VERSION 5.7 ;
  NOWIREEXTENSIONATPIN ON ;
  DIVIDERCHAR "/" ;
  BUSBITCHARS "[]" ;
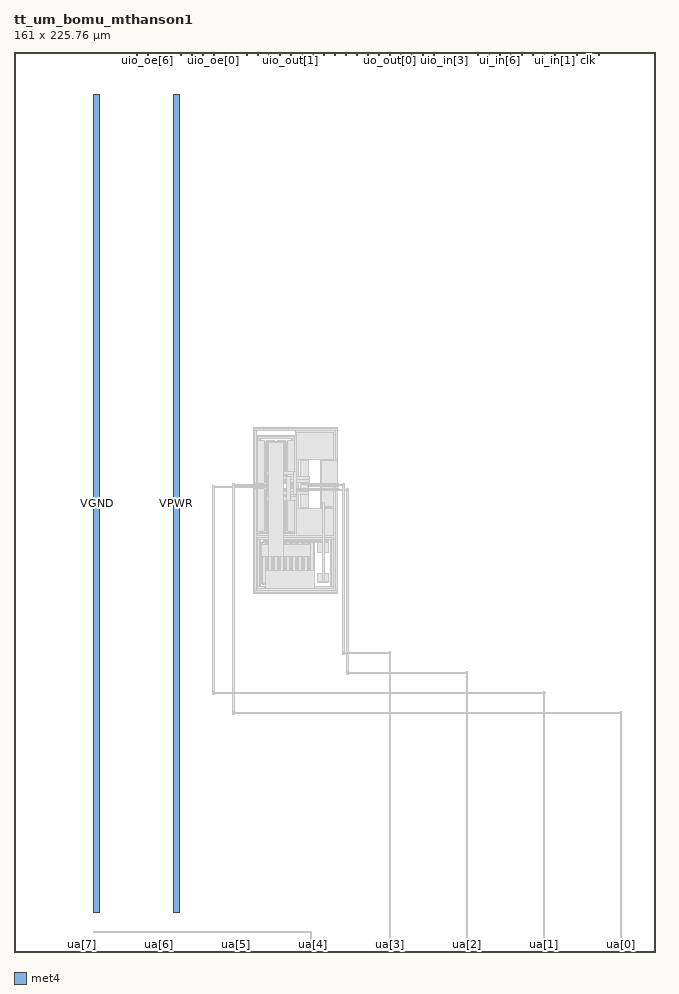
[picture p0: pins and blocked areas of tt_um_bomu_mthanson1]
MACRO tt_um_bomu_mthanson1
  CLASS BLOCK ;
  FOREIGN tt_um_bomu_mthanson1 ;
  ORIGIN 0.000 0.000 ;
  SIZE 161.000 BY 225.760 ;
  PIN clk
    DIRECTION INPUT ;
    USE SIGNAL ;
    PORT
      LAYER met4 ;
        RECT 143.830 224.760 144.130 225.760 ;
    END
  END clk
  PIN ena
    DIRECTION INPUT ;
    USE SIGNAL ;
    PORT
      LAYER met4 ;
        RECT 146.590 224.760 146.890 225.760 ;
    END
  END ena
  PIN rst_n
    DIRECTION INPUT ;
    USE SIGNAL ;
    PORT
      LAYER met4 ;
        RECT 141.070 224.760 141.370 225.760 ;
    END
  END rst_n
  PIN ua[0]
    DIRECTION INOUT ;
    USE SIGNAL ;
    ANTENNAGATEAREA 12.000000 ;
    PORT
      LAYER met4 ;
        RECT 151.810 0.000 152.710 1.000 ;
    END
  END ua[0]
  PIN ua[1]
    DIRECTION INOUT ;
    USE SIGNAL ;
    ANTENNAGATEAREA 12.000000 ;
    PORT
      LAYER met4 ;
        RECT 132.490 0.000 133.390 1.000 ;
    END
  END ua[1]
  PIN ua[2]
    DIRECTION INOUT ;
    USE SIGNAL ;
    ANTENNADIFFAREA 19.000000 ;
    PORT
      LAYER met4 ;
        RECT 113.170 0.000 114.070 1.000 ;
    END
  END ua[2]
  PIN ua[3]
    DIRECTION INOUT ;
    USE SIGNAL ;
    ANTENNADIFFAREA 19.000000 ;
    PORT
      LAYER met4 ;
        RECT 93.850 0.000 94.750 1.000 ;
    END
  END ua[3]
  PIN ua[4]
    DIRECTION INOUT ;
    USE SIGNAL ;
    PORT
      LAYER met4 ;
        RECT 74.530 0.000 75.430 1.000 ;
    END
  END ua[4]
  PIN ua[5]
    DIRECTION INOUT ;
    USE SIGNAL ;
    PORT
      LAYER met4 ;
        RECT 55.210 0.000 56.110 1.000 ;
    END
  END ua[5]
  PIN ua[6]
    DIRECTION INOUT ;
    USE SIGNAL ;
    PORT
      LAYER met4 ;
        RECT 35.890 0.000 36.790 1.000 ;
    END
  END ua[6]
  PIN ua[7]
    DIRECTION INOUT ;
    USE SIGNAL ;
    PORT
      LAYER met4 ;
        RECT 16.570 0.000 17.470 1.000 ;
    END
  END ua[7]
  PIN ui_in[0]
    DIRECTION INPUT ;
    USE SIGNAL ;
    PORT
      LAYER met4 ;
        RECT 138.310 224.760 138.610 225.760 ;
    END
  END ui_in[0]
  PIN ui_in[1]
    DIRECTION INPUT ;
    USE SIGNAL ;
    PORT
      LAYER met4 ;
        RECT 135.550 224.760 135.850 225.760 ;
    END
  END ui_in[1]
  PIN ui_in[2]
    DIRECTION INPUT ;
    USE SIGNAL ;
    PORT
      LAYER met4 ;
        RECT 132.790 224.760 133.090 225.760 ;
    END
  END ui_in[2]
  PIN ui_in[3]
    DIRECTION INPUT ;
    USE SIGNAL ;
    PORT
      LAYER met4 ;
        RECT 130.030 224.760 130.330 225.760 ;
    END
  END ui_in[3]
  PIN ui_in[4]
    DIRECTION INPUT ;
    USE SIGNAL ;
    PORT
      LAYER met4 ;
        RECT 127.270 224.760 127.570 225.760 ;
    END
  END ui_in[4]
  PIN ui_in[5]
    DIRECTION INPUT ;
    USE SIGNAL ;
    PORT
      LAYER met4 ;
        RECT 124.510 224.760 124.810 225.760 ;
    END
  END ui_in[5]
  PIN ui_in[6]
    DIRECTION INPUT ;
    USE SIGNAL ;
    PORT
      LAYER met4 ;
        RECT 121.750 224.760 122.050 225.760 ;
    END
  END ui_in[6]
  PIN ui_in[7]
    DIRECTION INPUT ;
    USE SIGNAL ;
    PORT
      LAYER met4 ;
        RECT 118.990 224.760 119.290 225.760 ;
    END
  END ui_in[7]
  PIN uio_in[0]
    DIRECTION INPUT ;
    USE SIGNAL ;
    PORT
      LAYER met4 ;
        RECT 116.230 224.760 116.530 225.760 ;
    END
  END uio_in[0]
  PIN uio_in[1]
    DIRECTION INPUT ;
    USE SIGNAL ;
    PORT
      LAYER met4 ;
        RECT 113.470 224.760 113.770 225.760 ;
    END
  END uio_in[1]
  PIN uio_in[2]
    DIRECTION INPUT ;
    USE SIGNAL ;
    PORT
      LAYER met4 ;
        RECT 110.710 224.760 111.010 225.760 ;
    END
  END uio_in[2]
  PIN uio_in[3]
    DIRECTION INPUT ;
    USE SIGNAL ;
    PORT
      LAYER met4 ;
        RECT 107.950 224.760 108.250 225.760 ;
    END
  END uio_in[3]
  PIN uio_in[4]
    DIRECTION INPUT ;
    USE SIGNAL ;
    PORT
      LAYER met4 ;
        RECT 105.190 224.760 105.490 225.760 ;
    END
  END uio_in[4]
  PIN uio_in[5]
    DIRECTION INPUT ;
    USE SIGNAL ;
    PORT
      LAYER met4 ;
        RECT 102.430 224.760 102.730 225.760 ;
    END
  END uio_in[5]
  PIN uio_in[6]
    DIRECTION INPUT ;
    USE SIGNAL ;
    PORT
      LAYER met4 ;
        RECT 99.670 224.760 99.970 225.760 ;
    END
  END uio_in[6]
  PIN uio_in[7]
    DIRECTION INPUT ;
    USE SIGNAL ;
    PORT
      LAYER met4 ;
        RECT 96.910 224.760 97.210 225.760 ;
    END
  END uio_in[7]
  PIN uio_oe[0]
    DIRECTION OUTPUT ;
    USE SIGNAL ;
    PORT
      LAYER met4 ;
        RECT 49.990 224.760 50.290 225.760 ;
    END
  END uio_oe[0]
  PIN uio_oe[1]
    DIRECTION OUTPUT ;
    USE SIGNAL ;
    PORT
      LAYER met4 ;
        RECT 47.230 224.760 47.530 225.760 ;
    END
  END uio_oe[1]
  PIN uio_oe[2]
    DIRECTION OUTPUT ;
    USE SIGNAL ;
    PORT
      LAYER met4 ;
        RECT 44.470 224.760 44.770 225.760 ;
    END
  END uio_oe[2]
  PIN uio_oe[3]
    DIRECTION OUTPUT ;
    USE SIGNAL ;
    PORT
      LAYER met4 ;
        RECT 41.710 224.760 42.010 225.760 ;
    END
  END uio_oe[3]
  PIN uio_oe[4]
    DIRECTION OUTPUT ;
    USE SIGNAL ;
    PORT
      LAYER met4 ;
        RECT 38.950 224.760 39.250 225.760 ;
    END
  END uio_oe[4]
  PIN uio_oe[5]
    DIRECTION OUTPUT ;
    USE SIGNAL ;
    PORT
      LAYER met4 ;
        RECT 36.190 224.760 36.490 225.760 ;
    END
  END uio_oe[5]
  PIN uio_oe[6]
    DIRECTION OUTPUT ;
    USE SIGNAL ;
    PORT
      LAYER met4 ;
        RECT 33.430 224.760 33.730 225.760 ;
    END
  END uio_oe[6]
  PIN uio_oe[7]
    DIRECTION OUTPUT ;
    USE SIGNAL ;
    PORT
      LAYER met4 ;
        RECT 30.670 224.760 30.970 225.760 ;
    END
  END uio_oe[7]
  PIN uio_out[0]
    DIRECTION OUTPUT ;
    USE SIGNAL ;
    PORT
      LAYER met4 ;
        RECT 72.070 224.760 72.370 225.760 ;
    END
  END uio_out[0]
  PIN uio_out[1]
    DIRECTION OUTPUT ;
    USE SIGNAL ;
    PORT
      LAYER met4 ;
        RECT 69.310 224.760 69.610 225.760 ;
    END
  END uio_out[1]
  PIN uio_out[2]
    DIRECTION OUTPUT ;
    USE SIGNAL ;
    PORT
      LAYER met4 ;
        RECT 66.550 224.760 66.850 225.760 ;
    END
  END uio_out[2]
  PIN uio_out[3]
    DIRECTION OUTPUT ;
    USE SIGNAL ;
    PORT
      LAYER met4 ;
        RECT 63.790 224.760 64.090 225.760 ;
    END
  END uio_out[3]
  PIN uio_out[4]
    DIRECTION OUTPUT ;
    USE SIGNAL ;
    PORT
      LAYER met4 ;
        RECT 61.030 224.760 61.330 225.760 ;
    END
  END uio_out[4]
  PIN uio_out[5]
    DIRECTION OUTPUT ;
    USE SIGNAL ;
    PORT
      LAYER met4 ;
        RECT 58.270 224.760 58.570 225.760 ;
    END
  END uio_out[5]
  PIN uio_out[6]
    DIRECTION OUTPUT ;
    USE SIGNAL ;
    PORT
      LAYER met4 ;
        RECT 55.510 224.760 55.810 225.760 ;
    END
  END uio_out[6]
  PIN uio_out[7]
    DIRECTION OUTPUT ;
    USE SIGNAL ;
    PORT
      LAYER met4 ;
        RECT 52.750 224.760 53.050 225.760 ;
    END
  END uio_out[7]
  PIN uo_out[0]
    DIRECTION OUTPUT ;
    USE SIGNAL ;
    PORT
      LAYER met4 ;
        RECT 94.150 224.760 94.450 225.760 ;
    END
  END uo_out[0]
  PIN uo_out[1]
    DIRECTION OUTPUT ;
    USE SIGNAL ;
    PORT
      LAYER met4 ;
        RECT 91.390 224.760 91.690 225.760 ;
    END
  END uo_out[1]
  PIN uo_out[2]
    DIRECTION OUTPUT ;
    USE SIGNAL ;
    PORT
      LAYER met4 ;
        RECT 88.630 224.760 88.930 225.760 ;
    END
  END uo_out[2]
  PIN uo_out[3]
    DIRECTION OUTPUT ;
    USE SIGNAL ;
    PORT
      LAYER met4 ;
        RECT 85.870 224.760 86.170 225.760 ;
    END
  END uo_out[3]
  PIN uo_out[4]
    DIRECTION OUTPUT ;
    USE SIGNAL ;
    PORT
      LAYER met4 ;
        RECT 83.110 224.760 83.410 225.760 ;
    END
  END uo_out[4]
  PIN uo_out[5]
    DIRECTION OUTPUT ;
    USE SIGNAL ;
    PORT
      LAYER met4 ;
        RECT 80.350 224.760 80.650 225.760 ;
    END
  END uo_out[5]
  PIN uo_out[6]
    DIRECTION OUTPUT ;
    USE SIGNAL ;
    PORT
      LAYER met4 ;
        RECT 77.590 224.760 77.890 225.760 ;
    END
  END uo_out[6]
  PIN uo_out[7]
    DIRECTION OUTPUT ;
    USE SIGNAL ;
    PORT
      LAYER met4 ;
        RECT 74.830 224.760 75.130 225.760 ;
    END
  END uo_out[7]
  PIN VGND
    USE GROUND ;
    PORT
      LAYER met4 ;
        RECT 20.000 10.000 21.500 215.000 ;
    END
  END VGND
  PIN VPWR
    USE POWER ;
    PORT
      LAYER met4 ;
        RECT 40.000 10.000 41.500 215.000 ;
    END
  END VPWR
  OBS
      LAYER pwell ;
        RECT 60.090 130.700 81.260 131.460 ;
        RECT 60.090 129.520 60.850 130.700 ;
        RECT 70.670 129.700 81.260 130.700 ;
        RECT 70.670 129.520 71.430 129.700 ;
        RECT 60.090 128.760 71.430 129.520 ;
        RECT 60.090 105.140 61.820 128.760 ;
        RECT 62.065 117.820 63.055 128.080 ;
        RECT 63.185 117.820 65.655 128.080 ;
        RECT 65.785 117.820 68.255 128.080 ;
        RECT 68.385 117.820 69.375 128.080 ;
        RECT 62.065 105.820 63.055 116.080 ;
        RECT 63.185 105.820 65.655 116.080 ;
        RECT 65.785 105.820 68.255 116.080 ;
        RECT 68.385 105.820 69.375 116.080 ;
        RECT 69.610 105.140 71.430 128.760 ;
        RECT 79.500 105.140 81.260 129.700 ;
        RECT 60.090 103.380 81.260 105.140 ;
        RECT 60.090 91.760 61.825 103.380 ;
        RECT 62.065 92.440 63.405 102.700 ;
        RECT 63.565 92.440 64.905 102.700 ;
        RECT 65.065 92.440 66.405 102.700 ;
        RECT 66.565 92.440 67.905 102.700 ;
        RECT 68.065 92.440 69.405 102.700 ;
        RECT 69.565 92.440 70.905 102.700 ;
        RECT 71.065 92.440 72.405 102.700 ;
        RECT 72.565 92.440 73.905 102.700 ;
        RECT 74.065 92.440 75.405 102.700 ;
        RECT 79.495 91.760 81.260 103.380 ;
        RECT 60.090 90.000 81.260 91.760 ;
      LAYER li1 ;
        RECT 60.220 130.830 81.130 131.330 ;
        RECT 60.220 90.630 60.720 130.830 ;
        RECT 70.800 129.830 80.130 130.330 ;
        RECT 61.190 128.890 70.240 129.390 ;
        RECT 61.190 105.010 61.690 128.890 ;
        RECT 62.340 128.140 62.780 128.310 ;
        RECT 63.460 128.140 65.380 128.310 ;
        RECT 66.060 128.140 67.980 128.310 ;
        RECT 68.660 128.140 69.100 128.310 ;
        RECT 62.255 117.930 62.425 127.970 ;
        RECT 62.695 117.930 62.865 127.970 ;
        RECT 63.375 117.930 63.545 127.970 ;
        RECT 63.855 117.930 64.025 127.970 ;
        RECT 64.335 117.930 64.505 127.970 ;
        RECT 64.815 117.930 64.985 127.970 ;
        RECT 65.295 117.930 65.465 127.970 ;
        RECT 65.975 117.930 66.145 127.970 ;
        RECT 66.455 117.930 66.625 127.970 ;
        RECT 66.935 117.930 67.105 127.970 ;
        RECT 67.415 117.930 67.585 127.970 ;
        RECT 67.895 117.930 68.065 127.970 ;
        RECT 68.575 117.930 68.745 127.970 ;
        RECT 69.015 117.930 69.185 127.970 ;
        RECT 62.340 117.590 62.780 117.760 ;
        RECT 63.460 117.590 65.380 117.760 ;
        RECT 66.060 117.590 67.980 117.760 ;
        RECT 68.660 117.590 69.100 117.760 ;
        RECT 62.340 116.140 62.780 116.310 ;
        RECT 63.460 116.140 65.380 116.310 ;
        RECT 66.060 116.140 67.980 116.310 ;
        RECT 68.660 116.140 69.100 116.310 ;
        RECT 62.255 105.930 62.425 115.970 ;
        RECT 62.695 105.930 62.865 115.970 ;
        RECT 63.375 105.930 63.545 115.970 ;
        RECT 63.855 105.930 64.025 115.970 ;
        RECT 64.335 105.930 64.505 115.970 ;
        RECT 64.815 105.930 64.985 115.970 ;
        RECT 65.295 105.930 65.465 115.970 ;
        RECT 65.975 105.930 66.145 115.970 ;
        RECT 66.455 105.930 66.625 115.970 ;
        RECT 66.935 105.930 67.105 115.970 ;
        RECT 67.415 105.930 67.585 115.970 ;
        RECT 67.895 105.930 68.065 115.970 ;
        RECT 68.575 105.930 68.745 115.970 ;
        RECT 69.015 105.930 69.185 115.970 ;
        RECT 62.340 105.590 62.780 105.760 ;
        RECT 63.460 105.590 65.380 105.760 ;
        RECT 66.060 105.590 67.980 105.760 ;
        RECT 68.660 105.590 69.100 105.760 ;
        RECT 69.740 105.010 70.240 128.890 ;
        RECT 61.190 104.510 70.240 105.010 ;
        RECT 70.800 105.010 71.300 129.830 ;
        RECT 71.800 123.600 73.960 129.330 ;
        RECT 76.970 123.600 79.130 129.330 ;
        RECT 71.800 117.570 73.960 123.300 ;
        RECT 76.970 117.570 79.130 123.300 ;
        RECT 71.800 111.540 73.960 117.270 ;
        RECT 76.970 111.540 79.130 117.270 ;
        RECT 71.800 105.510 73.960 111.240 ;
        RECT 76.970 105.510 79.130 111.240 ;
        RECT 79.630 105.010 80.130 129.830 ;
        RECT 70.800 104.510 80.130 105.010 ;
        RECT 61.195 103.510 80.125 104.010 ;
        RECT 61.195 91.630 61.695 103.510 ;
        RECT 62.340 102.760 63.130 102.930 ;
        RECT 63.840 102.760 64.630 102.930 ;
        RECT 65.340 102.760 66.130 102.930 ;
        RECT 66.840 102.760 67.630 102.930 ;
        RECT 68.340 102.760 69.130 102.930 ;
        RECT 69.840 102.760 70.630 102.930 ;
        RECT 71.340 102.760 72.130 102.930 ;
        RECT 72.840 102.760 73.630 102.930 ;
        RECT 74.340 102.760 75.130 102.930 ;
        RECT 62.255 92.550 62.425 102.590 ;
        RECT 63.045 92.550 63.215 102.590 ;
        RECT 63.755 92.550 63.925 102.590 ;
        RECT 64.545 92.550 64.715 102.590 ;
        RECT 65.255 92.550 65.425 102.590 ;
        RECT 66.045 92.550 66.215 102.590 ;
        RECT 66.755 92.550 66.925 102.590 ;
        RECT 67.545 92.550 67.715 102.590 ;
        RECT 68.255 92.550 68.425 102.590 ;
        RECT 69.045 92.550 69.215 102.590 ;
        RECT 69.755 92.550 69.925 102.590 ;
        RECT 70.545 92.550 70.715 102.590 ;
        RECT 71.255 92.550 71.425 102.590 ;
        RECT 72.045 92.550 72.215 102.590 ;
        RECT 72.755 92.550 72.925 102.590 ;
        RECT 73.545 92.550 73.715 102.590 ;
        RECT 74.255 92.550 74.425 102.590 ;
        RECT 75.045 92.550 75.215 102.590 ;
        RECT 76.025 100.200 78.875 102.360 ;
        RECT 76.025 92.770 78.875 94.930 ;
        RECT 62.340 92.210 63.130 92.380 ;
        RECT 63.840 92.210 64.630 92.380 ;
        RECT 65.340 92.210 66.130 92.380 ;
        RECT 66.840 92.210 67.630 92.380 ;
        RECT 68.340 92.210 69.130 92.380 ;
        RECT 69.840 92.210 70.630 92.380 ;
        RECT 71.340 92.210 72.130 92.380 ;
        RECT 72.840 92.210 73.630 92.380 ;
        RECT 74.340 92.210 75.130 92.380 ;
        RECT 79.625 91.630 80.125 103.510 ;
        RECT 61.195 91.130 80.125 91.630 ;
        RECT 80.630 90.630 81.130 130.830 ;
        RECT 60.220 90.130 81.130 90.630 ;
      LAYER met1 ;
        RECT 60.220 130.830 81.130 131.330 ;
        RECT 60.220 117.510 60.720 130.830 ;
        RECT 61.190 117.510 62.925 128.390 ;
        RECT 63.555 128.310 63.845 128.340 ;
        RECT 64.035 128.310 64.325 128.340 ;
        RECT 64.515 128.310 64.805 128.340 ;
        RECT 64.995 128.310 65.285 128.340 ;
        RECT 66.155 128.310 66.445 128.340 ;
        RECT 66.635 128.310 66.925 128.340 ;
        RECT 67.115 128.310 67.405 128.340 ;
        RECT 67.595 128.310 67.885 128.340 ;
        RECT 63.460 128.140 65.380 128.310 ;
        RECT 66.060 128.140 67.980 128.310 ;
        RECT 63.555 128.110 63.845 128.140 ;
        RECT 64.035 128.110 64.325 128.140 ;
        RECT 64.515 128.110 64.805 128.140 ;
        RECT 64.995 128.110 65.285 128.140 ;
        RECT 66.155 128.110 66.445 128.140 ;
        RECT 66.635 128.110 66.925 128.140 ;
        RECT 67.115 128.110 67.405 128.140 ;
        RECT 67.595 128.110 67.885 128.140 ;
        RECT 63.345 120.550 63.575 127.950 ;
        RECT 63.825 127.700 64.055 127.950 ;
        RECT 63.780 124.140 64.100 127.700 ;
        RECT 63.300 119.750 63.620 120.550 ;
        RECT 63.345 117.950 63.575 119.750 ;
        RECT 63.825 117.950 64.055 124.140 ;
        RECT 64.305 120.550 64.535 127.950 ;
        RECT 64.785 127.700 65.015 127.950 ;
        RECT 64.740 124.140 65.060 127.700 ;
        RECT 64.260 119.750 64.580 120.550 ;
        RECT 64.305 117.950 64.535 119.750 ;
        RECT 64.785 117.950 65.015 124.140 ;
        RECT 65.265 120.550 65.495 127.950 ;
        RECT 65.220 119.750 65.540 120.550 ;
        RECT 65.265 117.950 65.495 119.750 ;
        RECT 65.945 119.250 66.175 127.950 ;
        RECT 66.425 127.700 66.655 127.950 ;
        RECT 66.380 124.140 66.700 127.700 ;
        RECT 65.900 118.450 66.220 119.250 ;
        RECT 65.945 117.950 66.175 118.450 ;
        RECT 66.425 117.950 66.655 124.140 ;
        RECT 66.905 119.250 67.135 127.950 ;
        RECT 67.385 127.700 67.615 127.950 ;
        RECT 67.340 124.140 67.660 127.700 ;
        RECT 66.860 118.450 67.180 119.250 ;
        RECT 66.905 117.950 67.135 118.450 ;
        RECT 67.385 117.950 67.615 124.140 ;
        RECT 67.865 119.250 68.095 127.950 ;
        RECT 67.820 118.450 68.140 119.250 ;
        RECT 67.865 117.950 68.095 118.450 ;
        RECT 63.555 117.760 63.845 117.790 ;
        RECT 64.035 117.760 64.325 117.790 ;
        RECT 64.500 117.760 64.820 117.810 ;
        RECT 64.995 117.760 65.285 117.790 ;
        RECT 66.155 117.760 66.445 117.790 ;
        RECT 66.635 117.760 66.925 117.790 ;
        RECT 67.115 117.760 67.405 117.790 ;
        RECT 67.595 117.760 67.885 117.790 ;
        RECT 63.460 117.590 65.380 117.760 ;
        RECT 66.060 117.590 67.980 117.760 ;
        RECT 63.555 117.560 63.845 117.590 ;
        RECT 64.035 117.560 64.325 117.590 ;
        RECT 64.500 117.490 64.820 117.590 ;
        RECT 64.995 117.560 65.285 117.590 ;
        RECT 66.155 117.560 66.445 117.590 ;
        RECT 66.635 117.560 67.405 117.590 ;
        RECT 67.595 117.560 67.885 117.590 ;
        RECT 54.800 117.280 55.400 117.480 ;
        RECT 66.860 117.340 67.180 117.560 ;
        RECT 68.515 117.510 70.240 128.390 ;
        RECT 70.800 123.600 80.130 130.330 ;
        RECT 80.630 123.810 81.130 130.830 ;
        RECT 80.630 123.300 81.130 123.310 ;
        RECT 77.060 123.280 81.130 123.300 ;
        RECT 71.860 117.590 73.905 123.280 ;
        RECT 77.025 117.590 81.130 123.280 ;
        RECT 60.000 117.280 67.180 117.340 ;
        RECT 54.800 117.080 67.180 117.280 ;
        RECT 77.060 117.310 81.130 117.590 ;
        RECT 77.060 117.250 80.230 117.310 ;
        RECT 60.000 117.020 67.180 117.080 ;
        RECT 49.800 116.830 50.400 116.930 ;
        RECT 60.000 116.830 67.180 116.880 ;
        RECT 49.800 116.630 67.180 116.830 ;
        RECT 49.800 116.530 50.400 116.630 ;
        RECT 60.000 116.560 67.180 116.630 ;
        RECT 60.220 90.630 60.720 116.390 ;
        RECT 61.190 105.510 62.925 116.390 ;
        RECT 63.555 116.310 63.845 116.340 ;
        RECT 64.020 116.310 64.340 116.410 ;
        RECT 66.860 116.340 67.180 116.560 ;
        RECT 64.515 116.310 64.805 116.340 ;
        RECT 64.995 116.310 65.285 116.340 ;
        RECT 66.155 116.310 66.445 116.340 ;
        RECT 66.635 116.310 67.405 116.340 ;
        RECT 67.595 116.310 67.885 116.340 ;
        RECT 63.460 116.140 65.380 116.310 ;
        RECT 66.060 116.140 67.980 116.310 ;
        RECT 63.555 116.110 63.845 116.140 ;
        RECT 64.020 116.090 64.340 116.140 ;
        RECT 64.515 116.110 64.805 116.140 ;
        RECT 64.995 116.110 65.285 116.140 ;
        RECT 66.155 116.110 66.445 116.140 ;
        RECT 66.635 116.110 66.925 116.140 ;
        RECT 67.115 116.110 67.405 116.140 ;
        RECT 67.595 116.110 67.885 116.140 ;
        RECT 63.345 114.150 63.575 115.950 ;
        RECT 63.300 113.350 63.620 114.150 ;
        RECT 63.345 105.950 63.575 113.350 ;
        RECT 63.825 109.760 64.055 115.950 ;
        RECT 64.305 114.150 64.535 115.950 ;
        RECT 64.260 113.350 64.580 114.150 ;
        RECT 63.780 106.200 64.100 109.760 ;
        RECT 63.825 105.950 64.055 106.200 ;
        RECT 64.305 105.950 64.535 113.350 ;
        RECT 64.785 109.760 65.015 115.950 ;
        RECT 65.265 114.150 65.495 115.950 ;
        RECT 65.945 115.450 66.175 115.950 ;
        RECT 65.900 114.650 66.220 115.450 ;
        RECT 65.220 113.350 65.540 114.150 ;
        RECT 64.740 106.200 65.060 109.760 ;
        RECT 64.785 105.950 65.015 106.200 ;
        RECT 65.265 105.950 65.495 113.350 ;
        RECT 65.945 105.950 66.175 114.650 ;
        RECT 66.425 109.760 66.655 115.950 ;
        RECT 66.905 115.450 67.135 115.950 ;
        RECT 66.860 114.650 67.180 115.450 ;
        RECT 66.380 106.200 66.700 109.760 ;
        RECT 66.425 105.950 66.655 106.200 ;
        RECT 66.905 105.950 67.135 114.650 ;
        RECT 67.385 109.760 67.615 115.950 ;
        RECT 67.865 115.450 68.095 115.950 ;
        RECT 67.820 114.650 68.140 115.450 ;
        RECT 67.340 106.200 67.660 109.760 ;
        RECT 67.385 105.950 67.615 106.200 ;
        RECT 67.865 105.950 68.095 114.650 ;
        RECT 63.555 105.760 63.845 105.790 ;
        RECT 64.035 105.760 64.325 105.790 ;
        RECT 64.515 105.760 64.805 105.790 ;
        RECT 64.995 105.760 65.285 105.790 ;
        RECT 66.155 105.760 66.445 105.790 ;
        RECT 66.635 105.760 66.925 105.790 ;
        RECT 67.115 105.760 67.405 105.790 ;
        RECT 67.595 105.760 67.885 105.790 ;
        RECT 63.460 105.590 65.380 105.760 ;
        RECT 66.060 105.590 67.980 105.760 ;
        RECT 63.555 105.560 63.845 105.590 ;
        RECT 64.035 105.560 64.325 105.590 ;
        RECT 64.515 105.560 64.805 105.590 ;
        RECT 64.995 105.560 65.285 105.590 ;
        RECT 66.155 105.560 66.445 105.590 ;
        RECT 66.635 105.560 66.925 105.590 ;
        RECT 67.115 105.560 67.405 105.590 ;
        RECT 67.595 105.560 67.885 105.590 ;
        RECT 68.515 105.510 70.240 116.390 ;
        RECT 71.860 111.560 73.905 117.250 ;
        RECT 77.025 111.690 80.230 117.250 ;
        RECT 77.025 111.560 79.070 111.690 ;
        RECT 70.800 104.500 80.130 111.240 ;
        RECT 62.465 102.960 78.875 103.150 ;
        RECT 62.455 102.930 78.875 102.960 ;
        RECT 62.340 102.900 78.875 102.930 ;
        RECT 62.340 102.760 78.870 102.900 ;
        RECT 62.455 102.730 78.870 102.760 ;
        RECT 62.225 102.140 62.455 102.570 ;
        RECT 62.180 99.140 62.500 102.140 ;
        RECT 62.225 92.570 62.455 99.140 ;
        RECT 63.015 95.820 63.245 102.570 ;
        RECT 63.725 102.140 63.955 102.570 ;
        RECT 63.680 99.140 64.000 102.140 ;
        RECT 62.970 92.820 63.290 95.820 ;
        RECT 63.015 92.570 63.245 92.820 ;
        RECT 63.725 92.570 63.955 99.140 ;
        RECT 64.515 95.820 64.745 102.570 ;
        RECT 65.225 102.140 65.455 102.570 ;
        RECT 65.180 99.140 65.500 102.140 ;
        RECT 64.470 92.820 64.790 95.820 ;
        RECT 64.515 92.570 64.745 92.820 ;
        RECT 65.225 92.570 65.455 99.140 ;
        RECT 66.015 95.820 66.245 102.570 ;
        RECT 66.725 102.140 66.955 102.570 ;
        RECT 66.680 99.140 67.000 102.140 ;
        RECT 65.970 92.820 66.290 95.820 ;
        RECT 66.015 92.570 66.245 92.820 ;
        RECT 66.725 92.570 66.955 99.140 ;
        RECT 67.515 95.820 67.745 102.570 ;
        RECT 67.470 92.820 67.790 95.820 ;
        RECT 67.515 92.570 67.745 92.820 ;
        RECT 68.225 92.570 68.455 102.730 ;
        RECT 69.015 95.820 69.245 102.570 ;
        RECT 69.725 102.140 69.955 102.570 ;
        RECT 69.680 99.140 70.000 102.140 ;
        RECT 68.970 92.820 69.290 95.820 ;
        RECT 69.015 92.570 69.245 92.820 ;
        RECT 69.725 92.570 69.955 99.140 ;
        RECT 70.515 95.820 70.745 102.570 ;
        RECT 71.225 102.140 71.455 102.570 ;
        RECT 71.180 99.140 71.500 102.140 ;
        RECT 70.470 92.820 70.790 95.820 ;
        RECT 70.515 92.570 70.745 92.820 ;
        RECT 71.225 92.570 71.455 99.140 ;
        RECT 72.015 95.820 72.245 102.570 ;
        RECT 72.725 102.140 72.955 102.570 ;
        RECT 72.680 99.140 73.000 102.140 ;
        RECT 71.970 92.820 72.290 95.820 ;
        RECT 72.015 92.570 72.245 92.820 ;
        RECT 72.725 92.570 72.955 99.140 ;
        RECT 73.515 95.820 73.745 102.570 ;
        RECT 74.225 102.140 74.455 102.570 ;
        RECT 74.180 99.140 74.500 102.140 ;
        RECT 73.470 92.820 73.790 95.820 ;
        RECT 73.515 92.570 73.745 92.820 ;
        RECT 74.225 92.570 74.455 99.140 ;
        RECT 75.015 95.820 75.245 102.570 ;
        RECT 76.010 100.200 78.870 102.730 ;
        RECT 74.970 92.820 75.290 95.820 ;
        RECT 76.045 92.830 78.855 94.875 ;
        RECT 75.015 92.570 75.245 92.820 ;
        RECT 62.505 92.380 62.965 92.410 ;
        RECT 64.005 92.380 64.465 92.410 ;
        RECT 65.505 92.380 65.965 92.410 ;
        RECT 67.005 92.380 67.465 92.410 ;
        RECT 68.505 92.380 68.965 92.410 ;
        RECT 70.005 92.380 70.465 92.410 ;
        RECT 71.505 92.380 71.965 92.410 ;
        RECT 73.005 92.380 73.465 92.410 ;
        RECT 74.505 92.380 74.965 92.410 ;
        RECT 62.340 92.210 63.130 92.380 ;
        RECT 63.840 92.210 64.630 92.380 ;
        RECT 65.340 92.210 66.130 92.380 ;
        RECT 66.840 92.210 67.630 92.380 ;
        RECT 68.340 92.210 69.130 92.380 ;
        RECT 69.840 92.210 70.630 92.380 ;
        RECT 71.340 92.210 72.130 92.380 ;
        RECT 72.840 92.210 73.630 92.380 ;
        RECT 74.340 92.210 75.130 92.380 ;
        RECT 62.505 92.180 62.965 92.210 ;
        RECT 64.005 92.180 64.465 92.210 ;
        RECT 65.505 92.180 65.965 92.210 ;
        RECT 67.005 92.180 67.465 92.210 ;
        RECT 68.505 92.180 68.965 92.210 ;
        RECT 70.005 92.180 70.465 92.210 ;
        RECT 71.505 92.180 71.965 92.210 ;
        RECT 73.005 92.180 73.465 92.210 ;
        RECT 74.505 92.180 74.965 92.210 ;
        RECT 62.940 91.190 75.320 91.570 ;
        RECT 80.630 90.630 81.130 116.810 ;
        RECT 60.220 90.130 81.130 90.630 ;
      LAYER met2 ;
        RECT 63.775 124.120 65.065 127.720 ;
        RECT 66.375 124.120 67.665 127.760 ;
        RECT 63.300 119.750 70.860 120.550 ;
        RECT 73.700 119.250 74.190 119.270 ;
        RECT 65.900 118.450 74.190 119.250 ;
        RECT 54.800 117.080 55.400 117.480 ;
        RECT 49.800 116.530 50.400 116.930 ;
        RECT 64.020 116.090 64.340 117.340 ;
        RECT 64.500 116.560 64.820 117.810 ;
        RECT 68.460 117.650 74.190 118.450 ;
        RECT 73.700 117.450 74.190 117.650 ;
        RECT 73.700 117.260 81.330 117.450 ;
        RECT 82.400 117.260 83.000 117.460 ;
        RECT 73.700 117.060 83.000 117.260 ;
        RECT 73.700 116.850 81.330 117.060 ;
        RECT 70.060 116.050 81.330 116.250 ;
        RECT 83.400 116.050 84.000 116.250 ;
        RECT 70.060 115.850 84.000 116.050 ;
        RECT 70.060 115.650 81.330 115.850 ;
        RECT 70.060 115.450 73.960 115.650 ;
        RECT 65.900 114.650 73.960 115.450 ;
        RECT 63.300 113.350 70.800 114.150 ;
        RECT 63.775 106.180 65.065 109.780 ;
        RECT 66.375 106.180 67.665 109.780 ;
        RECT 62.180 102.130 63.410 102.140 ;
        RECT 67.760 102.130 74.500 102.140 ;
        RECT 62.180 99.140 74.500 102.130 ;
        RECT 62.970 91.130 75.290 95.820 ;
        RECT 77.460 93.400 77.960 112.770 ;
      LAYER met3 ;
        RECT 54.800 117.080 55.400 117.480 ;
        RECT 49.800 116.530 50.400 116.930 ;
        RECT 49.900 65.300 50.300 116.530 ;
        RECT 49.800 64.700 50.400 65.300 ;
        RECT 54.900 60.300 55.300 117.080 ;
        RECT 63.775 99.140 67.665 127.720 ;
        RECT 68.460 113.350 69.260 119.250 ;
        RECT 70.060 114.650 70.860 120.550 ;
        RECT 82.400 117.060 83.000 117.460 ;
        RECT 82.500 75.300 82.900 117.060 ;
        RECT 83.400 115.850 84.000 116.250 ;
        RECT 82.400 74.700 83.000 75.300 ;
        RECT 83.500 70.300 83.900 115.850 ;
        RECT 83.400 69.700 84.000 70.300 ;
        RECT 54.800 59.700 55.400 60.300 ;
        RECT 20.000 4.800 74.730 5.200 ;
        RECT 74.330 1.100 74.730 4.800 ;
        RECT 74.080 0.500 74.980 1.100 ;
        RECT 94.100 0.500 94.500 75.300 ;
        RECT 113.420 0.500 113.820 70.300 ;
        RECT 132.740 0.500 133.140 65.300 ;
        RECT 152.060 0.500 152.460 60.300 ;
      LAYER met4 ;
        RECT 82.400 75.200 83.000 75.300 ;
        RECT 94.100 75.200 94.500 75.300 ;
        RECT 82.400 74.800 94.500 75.200 ;
        RECT 82.400 74.700 83.000 74.800 ;
        RECT 94.100 74.700 94.500 74.800 ;
        RECT 83.400 70.200 84.000 70.300 ;
        RECT 113.420 70.200 113.820 70.300 ;
        RECT 83.400 69.800 113.820 70.200 ;
        RECT 83.400 69.700 84.000 69.800 ;
        RECT 113.420 69.700 113.820 69.800 ;
        RECT 49.800 65.200 50.400 65.300 ;
        RECT 132.740 65.200 133.140 65.300 ;
        RECT 49.800 64.800 133.200 65.200 ;
        RECT 49.800 64.700 50.400 64.800 ;
        RECT 132.740 64.700 133.140 64.800 ;
        RECT 54.800 60.200 55.400 60.300 ;
        RECT 152.060 60.200 152.460 60.300 ;
        RECT 54.800 59.800 152.500 60.200 ;
        RECT 54.800 59.700 55.400 59.800 ;
        RECT 152.060 59.700 152.460 59.800 ;
        RECT 20.000 4.800 21.500 5.200 ;
        RECT 74.080 1.000 74.980 1.100 ;
        RECT 94.100 1.000 94.500 1.100 ;
        RECT 113.420 1.000 113.820 1.100 ;
        RECT 132.740 1.000 133.140 1.100 ;
        RECT 152.060 1.000 152.460 1.100 ;
        RECT 74.080 0.500 74.530 1.000 ;
  END
END tt_um_bomu_mthanson1
END LIBRARY

